###############################################################
#  Generated by:      Cadence Innovus 21.14-s109_1
#  OS:                Linux x86_64(Host ID caen-vnc-mi06.engin.umich.edu)
#  Generated on:      Mon Apr  3 19:46:33 2023
#  Design:            decoder
#  Command:           write_lef_abstract /afs/umich.edu/class/eecs627/w23/groups/group4/CNN_LSTM/MEM/apr/decoder/data/decoder.lef -specifyTopLayer 4 -stripePin -PGpinLayers 4
###############################################################

VERSION 5.8 ;

BUSBITCHARS "[]" ;
DIVIDERCHAR "/" ;

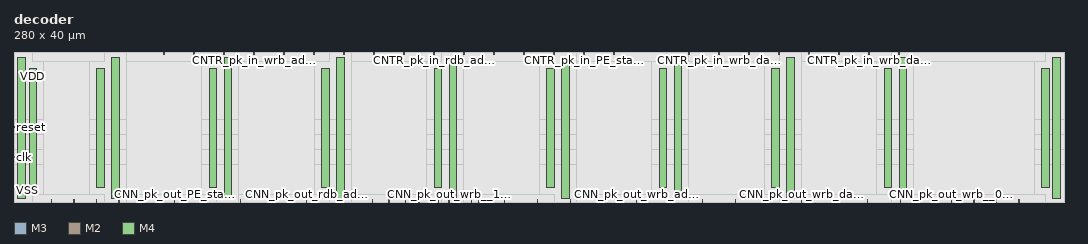
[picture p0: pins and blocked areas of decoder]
MACRO decoder
  CLASS BLOCK ;
  SIZE 280.000000 BY 40.000000 ;
  FOREIGN decoder 0.000000 0.000000 ;
  ORIGIN 0 0 ;
  SYMMETRY X Y R90 ;
  PIN clk
    DIRECTION INPUT ;
    USE SIGNAL ;
    ANTENNAPARTIALMETALAREA 1.46 LAYER M3  ;
    ANTENNAPARTIALMETALSIDEAREA 0.015 LAYER M3  ;
    ANTENNAMODEL OXIDE1 ;
    ANTENNAGATEAREA 0.2136 LAYER M3  ;
    ANTENNAMAXAREACAR 8.25187 LAYER M3  ;
    ANTENNAMAXSIDEAREACAR 0.0875468 LAYER M3  ;
    ANTENNAMAXCUTCAR 0.561798 LAYER V3  ;
    PORT
      LAYER M3 ;
        RECT 0.000000 11.900000 0.600000 12.100000 ;
    END
  END clk
  PIN reset
    DIRECTION INPUT ;
    USE SIGNAL ;
    ANTENNAPARTIALMETALAREA 12.66 LAYER M3  ;
    ANTENNAPARTIALMETALSIDEAREA 0.127 LAYER M3  ;
    ANTENNAMODEL OXIDE1 ;
    ANTENNAGATEAREA 0.4416 LAYER M3  ;
    ANTENNAMAXAREACAR 31.7705 LAYER M3  ;
    ANTENNAMAXSIDEAREACAR 0.316925 LAYER M3  ;
    ANTENNAMAXCUTCAR 0.48419 LAYER V3  ;
    PORT
      LAYER M3 ;
        RECT 0.000000 19.900000 0.600000 20.100000 ;
    END
  END reset
  PIN CNTR_pk_in_PE_state__2_
    DIRECTION INPUT ;
    USE SIGNAL ;
    ANTENNAPARTIALMETALAREA 1.66 LAYER M2  ;
    ANTENNAPARTIALMETALSIDEAREA 0.0166 LAYER M2  ;
    ANTENNAPARTIALCUTAREA 0.08 LAYER V2  ;
    ANTENNAPARTIALMETALAREA 0.36 LAYER M3  ;
    ANTENNAPARTIALMETALSIDEAREA 0.004 LAYER M3  ;
    ANTENNAMODEL OXIDE1 ;
    ANTENNAGATEAREA 0.0624 LAYER M3  ;
    ANTENNAMAXAREACAR 14.7692 LAYER M3  ;
    ANTENNAMAXSIDEAREACAR 0.155449 LAYER M3  ;
    ANTENNAMAXCUTCAR 2.5641 LAYER V3  ;
    PORT
      LAYER M2 ;
        RECT 135.900000 39.400000 136.100000 40.000000 ;
    END
  END CNTR_pk_in_PE_state__2_
  PIN CNTR_pk_in_PE_state__1_
    DIRECTION INPUT ;
    USE SIGNAL ;
    ANTENNAPARTIALMETALAREA 2.7 LAYER M2  ;
    ANTENNAPARTIALMETALSIDEAREA 0.027 LAYER M2  ;
    ANTENNAMODEL OXIDE1 ;
    ANTENNAGATEAREA 0.0624 LAYER M2  ;
    ANTENNAMAXAREACAR 49.0641 LAYER M2  ;
    ANTENNAMAXSIDEAREACAR 0.485577 LAYER M2  ;
    ANTENNAMAXCUTCAR 1.28205 LAYER V2  ;
    PORT
      LAYER M2 ;
        RECT 143.900000 39.400000 144.100000 40.000000 ;
    END
  END CNTR_pk_in_PE_state__1_
  PIN CNTR_pk_in_PE_state__0_
    DIRECTION INPUT ;
    USE SIGNAL ;
    ANTENNAPARTIALMETALAREA 2.62 LAYER M2  ;
    ANTENNAPARTIALMETALSIDEAREA 0.0262 LAYER M2  ;
    ANTENNAMODEL OXIDE1 ;
    ANTENNAGATEAREA 0.0624 LAYER M2  ;
    ANTENNAMAXAREACAR 47.7821 LAYER M2  ;
    ANTENNAMAXSIDEAREACAR 0.472756 LAYER M2  ;
    ANTENNAMAXCUTCAR 1.28205 LAYER V2  ;
    PORT
      LAYER M2 ;
        RECT 151.900000 39.400000 152.100000 40.000000 ;
    END
  END CNTR_pk_in_PE_state__0_
  PIN CNTR_pk_in_wrb_data__7_
    DIRECTION INPUT ;
    USE SIGNAL ;
    ANTENNAPARTIALMETALAREA 1.34 LAYER M2  ;
    ANTENNAPARTIALMETALSIDEAREA 0.0134 LAYER M2  ;
    ANTENNAPARTIALCUTAREA 0.08 LAYER V2  ;
    ANTENNAPARTIALMETALAREA 1.56 LAYER M3  ;
    ANTENNAPARTIALMETALSIDEAREA 0.016 LAYER M3  ;
    ANTENNAMODEL OXIDE1 ;
    ANTENNAGATEAREA 0.0624 LAYER M3  ;
    ANTENNAMAXAREACAR 39.1282 LAYER M3  ;
    ANTENNAMAXSIDEAREACAR 0.399038 LAYER M3  ;
    ANTENNAMAXCUTCAR 2.5641 LAYER V3  ;
    PORT
      LAYER M2 ;
        RECT 235.900000 39.400000 236.100000 40.000000 ;
    END
  END CNTR_pk_in_wrb_data__7_
  PIN CNTR_pk_in_wrb_data__6_
    DIRECTION INPUT ;
    USE SIGNAL ;
    ANTENNAPARTIALMETALAREA 2.7 LAYER M2  ;
    ANTENNAPARTIALMETALSIDEAREA 0.027 LAYER M2  ;
    ANTENNAMODEL OXIDE1 ;
    ANTENNAGATEAREA 0.0624 LAYER M2  ;
    ANTENNAMAXAREACAR 49.0641 LAYER M2  ;
    ANTENNAMAXSIDEAREACAR 0.485577 LAYER M2  ;
    ANTENNAMAXCUTCAR 1.28205 LAYER V2  ;
    PORT
      LAYER M2 ;
        RECT 227.900000 39.400000 228.100000 40.000000 ;
    END
  END CNTR_pk_in_wrb_data__6_
  PIN CNTR_pk_in_wrb_data__5_
    DIRECTION INPUT ;
    USE SIGNAL ;
    ANTENNAPARTIALMETALAREA 2.7 LAYER M2  ;
    ANTENNAPARTIALMETALSIDEAREA 0.027 LAYER M2  ;
    ANTENNAMODEL OXIDE1 ;
    ANTENNAGATEAREA 0.0624 LAYER M2  ;
    ANTENNAMAXAREACAR 49.0641 LAYER M2  ;
    ANTENNAMAXSIDEAREACAR 0.485577 LAYER M2  ;
    ANTENNAMAXCUTCAR 1.28205 LAYER V2  ;
    PORT
      LAYER M2 ;
        RECT 219.900000 39.400000 220.100000 40.000000 ;
    END
  END CNTR_pk_in_wrb_data__5_
  PIN CNTR_pk_in_wrb_data__4_
    DIRECTION INPUT ;
    USE SIGNAL ;
    ANTENNAPARTIALMETALAREA 2.7 LAYER M2  ;
    ANTENNAPARTIALMETALSIDEAREA 0.027 LAYER M2  ;
    ANTENNAMODEL OXIDE1 ;
    ANTENNAGATEAREA 0.0624 LAYER M2  ;
    ANTENNAMAXAREACAR 49.0641 LAYER M2  ;
    ANTENNAMAXSIDEAREACAR 0.485577 LAYER M2  ;
    ANTENNAMAXCUTCAR 1.28205 LAYER V2  ;
    PORT
      LAYER M2 ;
        RECT 211.900000 39.400000 212.100000 40.000000 ;
    END
  END CNTR_pk_in_wrb_data__4_
  PIN CNTR_pk_in_wrb_data__3_
    DIRECTION INPUT ;
    USE SIGNAL ;
    ANTENNAPARTIALMETALAREA 2.78 LAYER M2  ;
    ANTENNAPARTIALMETALSIDEAREA 0.0278 LAYER M2  ;
    ANTENNAMODEL OXIDE1 ;
    ANTENNAGATEAREA 0.0624 LAYER M2  ;
    ANTENNAMAXAREACAR 50.3462 LAYER M2  ;
    ANTENNAMAXSIDEAREACAR 0.498397 LAYER M2  ;
    ANTENNAMAXCUTCAR 1.28205 LAYER V2  ;
    PORT
      LAYER M2 ;
        RECT 203.900000 39.400000 204.100000 40.000000 ;
    END
  END CNTR_pk_in_wrb_data__3_
  PIN CNTR_pk_in_wrb_data__2_
    DIRECTION INPUT ;
    USE SIGNAL ;
    ANTENNAPARTIALMETALAREA 1.66 LAYER M2  ;
    ANTENNAPARTIALMETALSIDEAREA 0.0166 LAYER M2  ;
    ANTENNAPARTIALCUTAREA 0.08 LAYER V2  ;
    ANTENNAPARTIALMETALAREA 0.52 LAYER M3  ;
    ANTENNAPARTIALMETALSIDEAREA 0.0056 LAYER M3  ;
    ANTENNAMODEL OXIDE1 ;
    ANTENNAGATEAREA 0.0624 LAYER M3  ;
    ANTENNAMAXAREACAR 31.4359 LAYER M3  ;
    ANTENNAMAXSIDEAREACAR 0.322115 LAYER M3  ;
    ANTENNAMAXCUTCAR 2.5641 LAYER V3  ;
    PORT
      LAYER M2 ;
        RECT 195.900000 39.400000 196.100000 40.000000 ;
    END
  END CNTR_pk_in_wrb_data__2_
  PIN CNTR_pk_in_wrb_data__1_
    DIRECTION INPUT ;
    USE SIGNAL ;
    ANTENNAPARTIALMETALAREA 2.62 LAYER M2  ;
    ANTENNAPARTIALMETALSIDEAREA 0.0262 LAYER M2  ;
    ANTENNAMODEL OXIDE1 ;
    ANTENNAGATEAREA 0.0624 LAYER M2  ;
    ANTENNAMAXAREACAR 47.7821 LAYER M2  ;
    ANTENNAMAXSIDEAREACAR 0.472756 LAYER M2  ;
    ANTENNAMAXCUTCAR 1.28205 LAYER V2  ;
    PORT
      LAYER M2 ;
        RECT 187.900000 39.400000 188.100000 40.000000 ;
    END
  END CNTR_pk_in_wrb_data__1_
  PIN CNTR_pk_in_wrb_data__0_
    DIRECTION INPUT ;
    USE SIGNAL ;
    ANTENNAPARTIALMETALAREA 2.7 LAYER M2  ;
    ANTENNAPARTIALMETALSIDEAREA 0.027 LAYER M2  ;
    ANTENNAMODEL OXIDE1 ;
    ANTENNAGATEAREA 0.0624 LAYER M2  ;
    ANTENNAMAXAREACAR 49.0641 LAYER M2  ;
    ANTENNAMAXSIDEAREACAR 0.485577 LAYER M2  ;
    ANTENNAMAXCUTCAR 1.28205 LAYER V2  ;
    PORT
      LAYER M2 ;
        RECT 179.900000 39.400000 180.100000 40.000000 ;
    END
  END CNTR_pk_in_wrb_data__0_
  PIN CNTR_pk_in_wrb_addr__7_
    DIRECTION INPUT ;
    USE SIGNAL ;
    ANTENNAPARTIALMETALAREA 1.9 LAYER M2  ;
    ANTENNAPARTIALMETALSIDEAREA 0.019 LAYER M2  ;
    ANTENNAPARTIALCUTAREA 0.08 LAYER V2  ;
    ANTENNAPARTIALMETALAREA 5.76 LAYER M3  ;
    ANTENNAPARTIALMETALSIDEAREA 0.0584 LAYER M3  ;
    ANTENNAMODEL OXIDE1 ;
    ANTENNAGATEAREA 0.5184 LAYER M3  ;
    ANTENNAMAXAREACAR 17.4621 LAYER M3  ;
    ANTENNAMAXSIDEAREACAR 0.177783 LAYER M3  ;
    ANTENNAMAXCUTCAR 0.704225 LAYER V3  ;
    PORT
      LAYER M2 ;
        RECT 39.900000 39.400000 40.100000 40.000000 ;
    END
  END CNTR_pk_in_wrb_addr__7_
  PIN CNTR_pk_in_wrb_addr__6_
    DIRECTION INPUT ;
    USE SIGNAL ;
    ANTENNAPARTIALMETALAREA 1.42 LAYER M2  ;
    ANTENNAPARTIALMETALSIDEAREA 0.0142 LAYER M2  ;
    ANTENNAPARTIALCUTAREA 0.08 LAYER V2  ;
    ANTENNAPARTIALMETALAREA 1.4 LAYER M3  ;
    ANTENNAPARTIALMETALSIDEAREA 0.0144 LAYER M3  ;
    ANTENNAMODEL OXIDE1 ;
    ANTENNAGATEAREA 0.2208 LAYER M3  ;
    ANTENNAMAXAREACAR 21.8349 LAYER M3  ;
    ANTENNAMAXSIDEAREACAR 0.225215 LAYER M3  ;
    ANTENNAMAXCUTCAR 0.812769 LAYER V3  ;
    PORT
      LAYER M2 ;
        RECT 47.900000 39.400000 48.100000 40.000000 ;
    END
  END CNTR_pk_in_wrb_addr__6_
  PIN CNTR_pk_in_wrb_addr__5_
    DIRECTION INPUT ;
    USE SIGNAL ;
    ANTENNAPARTIALMETALAREA 1.34 LAYER M2  ;
    ANTENNAPARTIALMETALSIDEAREA 0.0134 LAYER M2  ;
    ANTENNAPARTIALCUTAREA 0.08 LAYER V2  ;
    ANTENNAPARTIALMETALAREA 1.16 LAYER M3  ;
    ANTENNAPARTIALMETALSIDEAREA 0.012 LAYER M3  ;
    ANTENNAMODEL OXIDE1 ;
    ANTENNAGATEAREA 0.0888 LAYER M3  ;
    ANTENNAMAXAREACAR 20.464 LAYER M3  ;
    ANTENNAMAXSIDEAREACAR 0.216892 LAYER M3  ;
    ANTENNAMAXCUTCAR 1.35135 LAYER V3  ;
    PORT
      LAYER M2 ;
        RECT 55.900000 39.400000 56.100000 40.000000 ;
    END
  END CNTR_pk_in_wrb_addr__5_
  PIN CNTR_pk_in_wrb_addr__4_
    DIRECTION INPUT ;
    USE SIGNAL ;
    ANTENNAPARTIALMETALAREA 1.9 LAYER M2  ;
    ANTENNAPARTIALMETALSIDEAREA 0.019 LAYER M2  ;
    ANTENNAMODEL OXIDE1 ;
    ANTENNAGATEAREA 0.1704 LAYER M2  ;
    ANTENNAMAXAREACAR 12.7277 LAYER M2  ;
    ANTENNAMAXSIDEAREACAR 0.127465 LAYER M2  ;
    ANTENNAPARTIALCUTAREA 0.08 LAYER V2  ;
    ANTENNAMAXCUTCAR 0.938967 LAYER V2  ;
    ANTENNAPARTIALMETALAREA 0.92 LAYER M3  ;
    ANTENNAPARTIALMETALSIDEAREA 0.0096 LAYER M3  ;
    ANTENNAGATEAREA 0.4512 LAYER M3  ;
    ANTENNAMAXAREACAR 14.7667 LAYER M3  ;
    ANTENNAMAXSIDEAREACAR 0.148741 LAYER M3  ;
    ANTENNAMAXCUTCAR 0.938967 LAYER V3  ;
    PORT
      LAYER M2 ;
        RECT 63.900000 39.400000 64.100000 40.000000 ;
    END
  END CNTR_pk_in_wrb_addr__4_
  PIN CNTR_pk_in_wrb_addr__3_
    DIRECTION INPUT ;
    USE SIGNAL ;
    ANTENNAPARTIALMETALAREA 2.0424 LAYER M2  ;
    ANTENNAPARTIALMETALSIDEAREA 0.02036 LAYER M2  ;
    ANTENNAPARTIALCUTAREA 0.08 LAYER V2  ;
    ANTENNAPARTIALMETALAREA 13 LAYER M3  ;
    ANTENNAPARTIALMETALSIDEAREA 0.1304 LAYER M3  ;
    ANTENNAPARTIALCUTAREA 0.04 LAYER V3  ;
    ANTENNAPARTIALMETALAREA 0.24 LAYER M4  ;
    ANTENNAPARTIALMETALSIDEAREA 0.0032 LAYER M4  ;
    ANTENNAMODEL OXIDE1 ;
    ANTENNAGATEAREA 0.0624 LAYER M4  ;
    ANTENNAMAXAREACAR 40.4103 LAYER M4  ;
    ANTENNAMAXSIDEAREACAR 0.424679 LAYER M4  ;
    ANTENNAMAXCUTCAR 3.20513 LAYER V4  ;
    PORT
      LAYER M2 ;
        RECT 71.920000 39.240000 72.080000 40.000000 ;
    END
  END CNTR_pk_in_wrb_addr__3_
  PIN CNTR_pk_in_wrb_addr__2_
    DIRECTION INPUT ;
    USE SIGNAL ;
    ANTENNAPARTIALMETALAREA 0.164 LAYER M2  ;
    ANTENNAPARTIALMETALSIDEAREA 0.00164 LAYER M2  ;
    ANTENNAPARTIALCUTAREA 0.08 LAYER V2  ;
    ANTENNAPARTIALMETALAREA 9.64 LAYER M3  ;
    ANTENNAPARTIALMETALSIDEAREA 0.0968 LAYER M3  ;
    ANTENNAPARTIALCUTAREA 0.04 LAYER V3  ;
    ANTENNAPARTIALMETALAREA 0.24 LAYER M4  ;
    ANTENNAPARTIALMETALSIDEAREA 0.0032 LAYER M4  ;
    ANTENNAMODEL OXIDE1 ;
    ANTENNAGATEAREA 0.0624 LAYER M4  ;
    ANTENNAMAXAREACAR 47.4615 LAYER M4  ;
    ANTENNAMAXSIDEAREACAR 0.501603 LAYER M4  ;
    ANTENNAMAXCUTCAR 3.20513 LAYER V4  ;
    PORT
      LAYER M2 ;
        RECT 79.920000 39.240000 80.080000 40.000000 ;
    END
  END CNTR_pk_in_wrb_addr__2_
  PIN CNTR_pk_in_wrb_addr__1_
    DIRECTION INPUT ;
    USE SIGNAL ;
    ANTENNAPARTIALMETALAREA 1.4824 LAYER M2  ;
    ANTENNAPARTIALMETALSIDEAREA 0.01476 LAYER M2  ;
    ANTENNAPARTIALCUTAREA 0.08 LAYER V2  ;
    ANTENNAPARTIALMETALAREA 6.8 LAYER M3  ;
    ANTENNAPARTIALMETALSIDEAREA 0.0688 LAYER M3  ;
    ANTENNAPARTIALCUTAREA 0.04 LAYER V3  ;
    ANTENNAPARTIALMETALAREA 0.24 LAYER M4  ;
    ANTENNAPARTIALMETALSIDEAREA 0.0032 LAYER M4  ;
    ANTENNAMODEL OXIDE1 ;
    ANTENNAGATEAREA 0.0624 LAYER M4  ;
    ANTENNAMAXAREACAR 36.5641 LAYER M4  ;
    ANTENNAMAXSIDEAREACAR 0.386218 LAYER M4  ;
    ANTENNAMAXCUTCAR 3.20513 LAYER V4  ;
    PORT
      LAYER M2 ;
        RECT 87.920000 39.240000 88.080000 40.000000 ;
    END
  END CNTR_pk_in_wrb_addr__1_
  PIN CNTR_pk_in_wrb_addr__0_
    DIRECTION INPUT ;
    USE SIGNAL ;
    ANTENNAPARTIALMETALAREA 2.46 LAYER M2  ;
    ANTENNAPARTIALMETALSIDEAREA 0.0246 LAYER M2  ;
    ANTENNAPARTIALCUTAREA 0.08 LAYER V2  ;
    ANTENNAPARTIALMETALAREA 5 LAYER M3  ;
    ANTENNAPARTIALMETALSIDEAREA 0.0504 LAYER M3  ;
    ANTENNAPARTIALCUTAREA 0.04 LAYER V3  ;
    ANTENNAPARTIALMETALAREA 0.24 LAYER M4  ;
    ANTENNAPARTIALMETALSIDEAREA 0.0032 LAYER M4  ;
    ANTENNAMODEL OXIDE1 ;
    ANTENNAGATEAREA 0.0624 LAYER M4  ;
    ANTENNAMAXAREACAR 31.4359 LAYER M4  ;
    ANTENNAMAXSIDEAREACAR 0.334936 LAYER M4  ;
    ANTENNAMAXCUTCAR 3.20513 LAYER V4  ;
    PORT
      LAYER M2 ;
        RECT 95.900000 39.400000 96.100000 40.000000 ;
    END
  END CNTR_pk_in_wrb_addr__0_
  PIN CNTR_pk_in_wrb_
    DIRECTION INPUT ;
    USE SIGNAL ;
    ANTENNAPARTIALMETALAREA 3.18 LAYER M2  ;
    ANTENNAPARTIALMETALSIDEAREA 0.0318 LAYER M2  ;
    ANTENNAPARTIALCUTAREA 0.08 LAYER V2  ;
    ANTENNAPARTIALMETALAREA 20.24 LAYER M3  ;
    ANTENNAPARTIALMETALSIDEAREA 0.2032 LAYER M3  ;
    ANTENNAMODEL OXIDE1 ;
    ANTENNAGATEAREA 0.4104 LAYER M3  ;
    ANTENNAMAXAREACAR 52.5131 LAYER M3  ;
    ANTENNAMAXSIDEAREACAR 0.536506 LAYER M3  ;
    ANTENNAMAXCUTCAR 1.72414 LAYER V3  ;
    PORT
      LAYER M2 ;
        RECT 159.900000 39.400000 160.100000 40.000000 ;
    END
  END CNTR_pk_in_wrb_
  PIN CNTR_pk_in_rdb_addr__3_
    DIRECTION INPUT ;
    USE SIGNAL ;
    ANTENNAPARTIALMETALAREA 1.5 LAYER M2  ;
    ANTENNAPARTIALMETALSIDEAREA 0.015 LAYER M2  ;
    ANTENNAPARTIALCUTAREA 0.08 LAYER V2  ;
    ANTENNAPARTIALMETALAREA 0.6 LAYER M3  ;
    ANTENNAPARTIALMETALSIDEAREA 0.0064 LAYER M3  ;
    ANTENNAMODEL OXIDE1 ;
    ANTENNAGATEAREA 0.0624 LAYER M3  ;
    ANTENNAMAXAREACAR 21.1795 LAYER M3  ;
    ANTENNAMAXSIDEAREACAR 0.219551 LAYER M3  ;
    ANTENNAMAXCUTCAR 2.5641 LAYER V3  ;
    PORT
      LAYER M2 ;
        RECT 103.900000 39.400000 104.100000 40.000000 ;
    END
  END CNTR_pk_in_rdb_addr__3_
  PIN CNTR_pk_in_rdb_addr__2_
    DIRECTION INPUT ;
    USE SIGNAL ;
    ANTENNAPARTIALMETALAREA 1.74 LAYER M2  ;
    ANTENNAPARTIALMETALSIDEAREA 0.0174 LAYER M2  ;
    ANTENNAMODEL OXIDE1 ;
    ANTENNAGATEAREA 0.0624 LAYER M2  ;
    ANTENNAMAXAREACAR 33.6795 LAYER M2  ;
    ANTENNAMAXSIDEAREACAR 0.331731 LAYER M2  ;
    ANTENNAMAXCUTCAR 1.28205 LAYER V2  ;
    PORT
      LAYER M2 ;
        RECT 111.900000 39.400000 112.100000 40.000000 ;
    END
  END CNTR_pk_in_rdb_addr__2_
  PIN CNTR_pk_in_rdb_addr__1_
    DIRECTION INPUT ;
    USE SIGNAL ;
    ANTENNAPARTIALMETALAREA 1.92 LAYER M2  ;
    ANTENNAPARTIALMETALSIDEAREA 0.0192 LAYER M2  ;
    ANTENNAMODEL OXIDE1 ;
    ANTENNAGATEAREA 0.0624 LAYER M2  ;
    ANTENNAMAXAREACAR 36.5641 LAYER M2  ;
    ANTENNAMAXSIDEAREACAR 0.360577 LAYER M2  ;
    ANTENNAMAXCUTCAR 1.28205 LAYER V2  ;
    PORT
      LAYER M2 ;
        RECT 119.900000 39.400000 120.100000 40.000000 ;
    END
  END CNTR_pk_in_rdb_addr__1_
  PIN CNTR_pk_in_rdb_addr__0_
    DIRECTION INPUT ;
    USE SIGNAL ;
    ANTENNAPARTIALMETALAREA 3.18 LAYER M2  ;
    ANTENNAPARTIALMETALSIDEAREA 0.0318 LAYER M2  ;
    ANTENNAMODEL OXIDE1 ;
    ANTENNAGATEAREA 0.0624 LAYER M2  ;
    ANTENNAMAXAREACAR 56.7564 LAYER M2  ;
    ANTENNAMAXSIDEAREACAR 0.5625 LAYER M2  ;
    ANTENNAMAXCUTCAR 1.28205 LAYER V2  ;
    PORT
      LAYER M2 ;
        RECT 127.900000 39.400000 128.100000 40.000000 ;
    END
  END CNTR_pk_in_rdb_addr__0_
  PIN CNN_pk_out_PE_state__2_
    DIRECTION OUTPUT ;
    USE SIGNAL ;
    ANTENNAPARTIALMETALAREA 1.26 LAYER M2  ;
    ANTENNAPARTIALMETALSIDEAREA 0.0126 LAYER M2  ;
    ANTENNAPARTIALCUTAREA 0.08 LAYER V2  ;
    ANTENNADIFFAREA 2.014 LAYER M3  ;
    ANTENNAPARTIALMETALAREA 7.8 LAYER M3  ;
    ANTENNAPARTIALMETALSIDEAREA 0.0784 LAYER M3  ;
    PORT
      LAYER M2 ;
        RECT 60.300000 0.000000 60.500000 0.600000 ;
    END
  END CNN_pk_out_PE_state__2_
  PIN CNN_pk_out_PE_state__1_
    DIRECTION OUTPUT ;
    USE SIGNAL ;
    ANTENNAPARTIALMETALAREA 1.42 LAYER M2  ;
    ANTENNAPARTIALMETALSIDEAREA 0.0142 LAYER M2  ;
    ANTENNAPARTIALCUTAREA 0.08 LAYER V2  ;
    ANTENNADIFFAREA 2.014 LAYER M3  ;
    ANTENNAPARTIALMETALAREA 3.8 LAYER M3  ;
    ANTENNAPARTIALMETALSIDEAREA 0.0384 LAYER M3  ;
    PORT
      LAYER M2 ;
        RECT 51.500000 0.000000 51.700000 0.600000 ;
    END
  END CNN_pk_out_PE_state__1_
  PIN CNN_pk_out_PE_state__0_
    DIRECTION OUTPUT ;
    USE SIGNAL ;
    ANTENNADIFFAREA 2.014 LAYER M2  ;
    ANTENNAPARTIALMETALAREA 5.58 LAYER M2  ;
    ANTENNAPARTIALMETALSIDEAREA 0.0558 LAYER M2  ;
    PORT
      LAYER M2 ;
        RECT 42.700000 0.000000 42.900000 0.600000 ;
    END
  END CNN_pk_out_PE_state__0_
  PIN CNN_pk_out_wrb_data__7_
    DIRECTION OUTPUT ;
    USE SIGNAL ;
    ANTENNAPARTIALMETALAREA 1.66 LAYER M2  ;
    ANTENNAPARTIALMETALSIDEAREA 0.0166 LAYER M2  ;
    ANTENNAPARTIALCUTAREA 0.08 LAYER V2  ;
    ANTENNADIFFAREA 2.014 LAYER M3  ;
    ANTENNAPARTIALMETALAREA 1.16 LAYER M3  ;
    ANTENNAPARTIALMETALSIDEAREA 0.012 LAYER M3  ;
    PORT
      LAYER M2 ;
        RECT 236.300000 0.000000 236.500000 0.600000 ;
    END
  END CNN_pk_out_wrb_data__7_
  PIN CNN_pk_out_wrb_data__6_
    DIRECTION OUTPUT ;
    USE SIGNAL ;
    ANTENNAPARTIALMETALAREA 2.94 LAYER M2  ;
    ANTENNAPARTIALMETALSIDEAREA 0.0294 LAYER M2  ;
    ANTENNAPARTIALCUTAREA 0.08 LAYER V2  ;
    ANTENNADIFFAREA 2.014 LAYER M3  ;
    ANTENNAPARTIALMETALAREA 0.68 LAYER M3  ;
    ANTENNAPARTIALMETALSIDEAREA 0.0072 LAYER M3  ;
    PORT
      LAYER M2 ;
        RECT 227.500000 0.000000 227.700000 0.600000 ;
    END
  END CNN_pk_out_wrb_data__6_
  PIN CNN_pk_out_wrb_data__5_
    DIRECTION OUTPUT ;
    USE SIGNAL ;
    ANTENNAPARTIALMETALAREA 3.74 LAYER M2  ;
    ANTENNAPARTIALMETALSIDEAREA 0.0374 LAYER M2  ;
    ANTENNAPARTIALCUTAREA 0.08 LAYER V2  ;
    ANTENNADIFFAREA 2.014 LAYER M3  ;
    ANTENNAPARTIALMETALAREA 0.76 LAYER M3  ;
    ANTENNAPARTIALMETALSIDEAREA 0.008 LAYER M3  ;
    PORT
      LAYER M2 ;
        RECT 218.700000 0.000000 218.900000 0.600000 ;
    END
  END CNN_pk_out_wrb_data__5_
  PIN CNN_pk_out_wrb_data__4_
    DIRECTION OUTPUT ;
    USE SIGNAL ;
    ANTENNAPARTIALMETALAREA 3.58 LAYER M2  ;
    ANTENNAPARTIALMETALSIDEAREA 0.0358 LAYER M2  ;
    ANTENNAPARTIALCUTAREA 0.08 LAYER V2  ;
    ANTENNADIFFAREA 2.014 LAYER M3  ;
    ANTENNAPARTIALMETALAREA 0.76 LAYER M3  ;
    ANTENNAPARTIALMETALSIDEAREA 0.008 LAYER M3  ;
    PORT
      LAYER M2 ;
        RECT 209.900000 0.000000 210.100000 0.600000 ;
    END
  END CNN_pk_out_wrb_data__4_
  PIN CNN_pk_out_wrb_data__3_
    DIRECTION OUTPUT ;
    USE SIGNAL ;
    ANTENNADIFFAREA 2.014 LAYER M2  ;
    ANTENNAPARTIALMETALAREA 4.56 LAYER M2  ;
    ANTENNAPARTIALMETALSIDEAREA 0.0456 LAYER M2  ;
    PORT
      LAYER M2 ;
        RECT 201.100000 0.000000 201.300000 0.600000 ;
    END
  END CNN_pk_out_wrb_data__3_
  PIN CNN_pk_out_wrb_data__2_
    DIRECTION OUTPUT ;
    USE SIGNAL ;
    ANTENNADIFFAREA 2.014 LAYER M2  ;
    ANTENNAPARTIALMETALAREA 4.06 LAYER M2  ;
    ANTENNAPARTIALMETALSIDEAREA 0.0406 LAYER M2  ;
    PORT
      LAYER M2 ;
        RECT 192.300000 0.000000 192.500000 0.600000 ;
    END
  END CNN_pk_out_wrb_data__2_
  PIN CNN_pk_out_wrb_data__1_
    DIRECTION OUTPUT ;
    USE SIGNAL ;
    ANTENNAPARTIALMETALAREA 3.74 LAYER M2  ;
    ANTENNAPARTIALMETALSIDEAREA 0.0374 LAYER M2  ;
    ANTENNAPARTIALCUTAREA 0.08 LAYER V2  ;
    ANTENNADIFFAREA 2.014 LAYER M3  ;
    ANTENNAPARTIALMETALAREA 0.92 LAYER M3  ;
    ANTENNAPARTIALMETALSIDEAREA 0.0096 LAYER M3  ;
    PORT
      LAYER M2 ;
        RECT 183.500000 0.000000 183.700000 0.600000 ;
    END
  END CNN_pk_out_wrb_data__1_
  PIN CNN_pk_out_wrb_data__0_
    DIRECTION OUTPUT ;
    USE SIGNAL ;
    ANTENNADIFFAREA 2.014 LAYER M2  ;
    ANTENNAPARTIALMETALAREA 4.38 LAYER M2  ;
    ANTENNAPARTIALMETALSIDEAREA 0.0438 LAYER M2  ;
    PORT
      LAYER M2 ;
        RECT 174.700000 0.000000 174.900000 0.600000 ;
    END
  END CNN_pk_out_wrb_data__0_
  PIN CNN_pk_out_wrb_addr__3_
    DIRECTION OUTPUT ;
    USE SIGNAL ;
    ANTENNADIFFAREA 2.014 LAYER M2  ;
    ANTENNAPARTIALMETALAREA 4.16 LAYER M2  ;
    ANTENNAPARTIALMETALSIDEAREA 0.0416 LAYER M2  ;
    PORT
      LAYER M2 ;
        RECT 165.900000 0.000000 166.100000 0.600000 ;
    END
  END CNN_pk_out_wrb_addr__3_
  PIN CNN_pk_out_wrb_addr__2_
    DIRECTION OUTPUT ;
    USE SIGNAL ;
    ANTENNAPARTIALMETALAREA 3.82 LAYER M2  ;
    ANTENNAPARTIALMETALSIDEAREA 0.0382 LAYER M2  ;
    ANTENNAPARTIALCUTAREA 0.08 LAYER V2  ;
    ANTENNADIFFAREA 2.014 LAYER M3  ;
    ANTENNAPARTIALMETALAREA 0.76 LAYER M3  ;
    ANTENNAPARTIALMETALSIDEAREA 0.008 LAYER M3  ;
    PORT
      LAYER M2 ;
        RECT 157.100000 0.000000 157.300000 0.600000 ;
    END
  END CNN_pk_out_wrb_addr__2_
  PIN CNN_pk_out_wrb_addr__1_
    DIRECTION OUTPUT ;
    USE SIGNAL ;
    ANTENNAPARTIALMETALAREA 2.86 LAYER M2  ;
    ANTENNAPARTIALMETALSIDEAREA 0.0286 LAYER M2  ;
    ANTENNAPARTIALCUTAREA 0.08 LAYER V2  ;
    ANTENNADIFFAREA 2.014 LAYER M3  ;
    ANTENNAPARTIALMETALAREA 0.68 LAYER M3  ;
    ANTENNAPARTIALMETALSIDEAREA 0.0072 LAYER M3  ;
    PORT
      LAYER M2 ;
        RECT 148.300000 0.000000 148.500000 0.600000 ;
    END
  END CNN_pk_out_wrb_addr__1_
  PIN CNN_pk_out_wrb_addr__0_
    DIRECTION OUTPUT ;
    USE SIGNAL ;
    ANTENNAPARTIALMETALAREA 2.78 LAYER M2  ;
    ANTENNAPARTIALMETALSIDEAREA 0.0278 LAYER M2  ;
    ANTENNAPARTIALCUTAREA 0.08 LAYER V2  ;
    ANTENNADIFFAREA 2.014 LAYER M3  ;
    ANTENNAPARTIALMETALAREA 0.6 LAYER M3  ;
    ANTENNAPARTIALMETALSIDEAREA 0.0064 LAYER M3  ;
    PORT
      LAYER M2 ;
        RECT 139.500000 0.000000 139.700000 0.600000 ;
    END
  END CNN_pk_out_wrb_addr__0_
  PIN CNN_pk_out_wrb__3__3_
    DIRECTION OUTPUT ;
    USE SIGNAL ;
    ANTENNAPARTIALMETALAREA 1.42 LAYER M2  ;
    ANTENNAPARTIALMETALSIDEAREA 0.0142 LAYER M2  ;
    ANTENNAPARTIALCUTAREA 0.08 LAYER V2  ;
    ANTENNADIFFAREA 2.172 LAYER M3  ;
    ANTENNAPARTIALMETALAREA 2.04 LAYER M3  ;
    ANTENNAPARTIALMETALSIDEAREA 0.0208 LAYER M3  ;
    PORT
      LAYER M2 ;
        RECT 130.700000 0.000000 130.900000 0.600000 ;
    END
  END CNN_pk_out_wrb__3__3_
  PIN CNN_pk_out_wrb__3__2_
    DIRECTION OUTPUT ;
    USE SIGNAL ;
    ANTENNADIFFAREA 2.172 LAYER M2  ;
    ANTENNAPARTIALMETALAREA 2.78 LAYER M2  ;
    ANTENNAPARTIALMETALSIDEAREA 0.0278 LAYER M2  ;
    PORT
      LAYER M2 ;
        RECT 121.900000 0.000000 122.100000 0.600000 ;
    END
  END CNN_pk_out_wrb__3__2_
  PIN CNN_pk_out_wrb__3__1_
    DIRECTION OUTPUT ;
    USE SIGNAL ;
    ANTENNAPARTIALMETALAREA 1.26 LAYER M2  ;
    ANTENNAPARTIALMETALSIDEAREA 0.0126 LAYER M2  ;
    ANTENNAPARTIALCUTAREA 0.08 LAYER V2  ;
    ANTENNADIFFAREA 3.196 LAYER M3  ;
    ANTENNAPARTIALMETALAREA 1.72 LAYER M3  ;
    ANTENNAPARTIALMETALSIDEAREA 0.0176 LAYER M3  ;
    PORT
      LAYER M2 ;
        RECT 113.100000 0.000000 113.300000 0.600000 ;
    END
  END CNN_pk_out_wrb__3__1_
  PIN CNN_pk_out_wrb__3__0_
    DIRECTION OUTPUT ;
    USE SIGNAL ;
    ANTENNAPARTIALMETALAREA 1.98 LAYER M2  ;
    ANTENNAPARTIALMETALSIDEAREA 0.0198 LAYER M2  ;
    ANTENNAPARTIALCUTAREA 0.04 LAYER V2  ;
    ANTENNADIFFAREA 3.196 LAYER M3  ;
    ANTENNAPARTIALMETALAREA 0.28 LAYER M3  ;
    ANTENNAPARTIALMETALSIDEAREA 0.0032 LAYER M3  ;
    PORT
      LAYER M2 ;
        RECT 104.300000 0.000000 104.500000 0.600000 ;
    END
  END CNN_pk_out_wrb__3__0_
  PIN CNN_pk_out_wrb__2__3_
    DIRECTION OUTPUT ;
    USE SIGNAL ;
    ANTENNAPARTIALMETALAREA 1.34 LAYER M2  ;
    ANTENNAPARTIALMETALSIDEAREA 0.0134 LAYER M2  ;
    ANTENNAPARTIALCUTAREA 0.08 LAYER V2  ;
    ANTENNADIFFAREA 2.172 LAYER M3  ;
    ANTENNAPARTIALMETALAREA 1.48 LAYER M3  ;
    ANTENNAPARTIALMETALSIDEAREA 0.0152 LAYER M3  ;
    PORT
      LAYER M2 ;
        RECT 27.900000 0.000000 28.100000 0.600000 ;
    END
  END CNN_pk_out_wrb__2__3_
  PIN CNN_pk_out_wrb__2__2_
    DIRECTION OUTPUT ;
    USE SIGNAL ;
    ANTENNAPARTIALMETALAREA 2.54 LAYER M2  ;
    ANTENNAPARTIALMETALSIDEAREA 0.0254 LAYER M2  ;
    ANTENNAPARTIALCUTAREA 0.08 LAYER V2  ;
    ANTENNADIFFAREA 2.172 LAYER M3  ;
    ANTENNAPARTIALMETALAREA 2.76 LAYER M3  ;
    ANTENNAPARTIALMETALSIDEAREA 0.028 LAYER M3  ;
    PORT
      LAYER M2 ;
        RECT 21.900000 0.000000 22.100000 0.600000 ;
    END
  END CNN_pk_out_wrb__2__2_
  PIN CNN_pk_out_wrb__2__1_
    DIRECTION OUTPUT ;
    USE SIGNAL ;
    ANTENNAPARTIALMETALAREA 1.5 LAYER M2  ;
    ANTENNAPARTIALMETALSIDEAREA 0.015 LAYER M2  ;
    ANTENNAPARTIALCUTAREA 0.08 LAYER V2  ;
    ANTENNADIFFAREA 3.196 LAYER M3  ;
    ANTENNAPARTIALMETALAREA 6.12 LAYER M3  ;
    ANTENNAPARTIALMETALSIDEAREA 0.0616 LAYER M3  ;
    PORT
      LAYER M2 ;
        RECT 15.900000 0.000000 16.100000 0.600000 ;
    END
  END CNN_pk_out_wrb__2__1_
  PIN CNN_pk_out_wrb__2__0_
    DIRECTION OUTPUT ;
    USE SIGNAL ;
    ANTENNAPARTIALMETALAREA 0.7 LAYER M2  ;
    ANTENNAPARTIALMETALSIDEAREA 0.007 LAYER M2  ;
    ANTENNAPARTIALCUTAREA 0.08 LAYER V2  ;
    ANTENNADIFFAREA 3.196 LAYER M3  ;
    ANTENNAPARTIALMETALAREA 7.56 LAYER M3  ;
    ANTENNAPARTIALMETALSIDEAREA 0.076 LAYER M3  ;
    PORT
      LAYER M2 ;
        RECT 9.900000 0.000000 10.100000 0.600000 ;
    END
  END CNN_pk_out_wrb__2__0_
  PIN CNN_pk_out_wrb__1__3_
    DIRECTION OUTPUT ;
    USE SIGNAL ;
    ANTENNADIFFAREA 2.172 LAYER M2  ;
    ANTENNAPARTIALMETALAREA 2.62 LAYER M2  ;
    ANTENNAPARTIALMETALSIDEAREA 0.0262 LAYER M2  ;
    PORT
      LAYER M2 ;
        RECT 123.900000 0.000000 124.100000 0.600000 ;
    END
  END CNN_pk_out_wrb__1__3_
  PIN CNN_pk_out_wrb__1__2_
    DIRECTION OUTPUT ;
    USE SIGNAL ;
    ANTENNADIFFAREA 2.172 LAYER M2  ;
    ANTENNAPARTIALMETALAREA 1.5 LAYER M2  ;
    ANTENNAPARTIALMETALSIDEAREA 0.015 LAYER M2  ;
    PORT
      LAYER M2 ;
        RECT 115.900000 0.000000 116.100000 0.600000 ;
    END
  END CNN_pk_out_wrb__1__2_
  PIN CNN_pk_out_wrb__1__1_
    DIRECTION OUTPUT ;
    USE SIGNAL ;
    ANTENNAPARTIALMETALAREA 1.98 LAYER M2  ;
    ANTENNAPARTIALMETALSIDEAREA 0.0198 LAYER M2  ;
    ANTENNAPARTIALCUTAREA 0.08 LAYER V2  ;
    ANTENNADIFFAREA 3.196 LAYER M3  ;
    ANTENNAPARTIALMETALAREA 0.52 LAYER M3  ;
    ANTENNAPARTIALMETALSIDEAREA 0.0056 LAYER M3  ;
    PORT
      LAYER M2 ;
        RECT 107.900000 0.000000 108.100000 0.600000 ;
    END
  END CNN_pk_out_wrb__1__1_
  PIN CNN_pk_out_wrb__1__0_
    DIRECTION OUTPUT ;
    USE SIGNAL ;
    ANTENNAPARTIALMETALAREA 1.5 LAYER M2  ;
    ANTENNAPARTIALMETALSIDEAREA 0.015 LAYER M2  ;
    ANTENNAPARTIALCUTAREA 0.04 LAYER V2  ;
    ANTENNADIFFAREA 3.196 LAYER M3  ;
    ANTENNAPARTIALMETALAREA 0.84 LAYER M3  ;
    ANTENNAPARTIALMETALSIDEAREA 0.0088 LAYER M3  ;
    PORT
      LAYER M2 ;
        RECT 99.900000 0.000000 100.100000 0.600000 ;
    END
  END CNN_pk_out_wrb__1__0_
  PIN CNN_pk_out_wrb__0__3_
    DIRECTION OUTPUT ;
    USE SIGNAL ;
    ANTENNAPARTIALMETALAREA 2.46 LAYER M2  ;
    ANTENNAPARTIALMETALSIDEAREA 0.0246 LAYER M2  ;
    ANTENNAPARTIALCUTAREA 0.08 LAYER V2  ;
    ANTENNADIFFAREA 2.848 LAYER M3  ;
    ANTENNAPARTIALMETALAREA 23.48 LAYER M3  ;
    ANTENNAPARTIALMETALSIDEAREA 0.2352 LAYER M3  ;
    PORT
      LAYER M2 ;
        RECT 267.900000 0.000000 268.100000 0.600000 ;
    END
  END CNN_pk_out_wrb__0__3_
  PIN CNN_pk_out_wrb__0__2_
    DIRECTION OUTPUT ;
    USE SIGNAL ;
    ANTENNAPARTIALMETALAREA 1.42 LAYER M2  ;
    ANTENNAPARTIALMETALSIDEAREA 0.0142 LAYER M2  ;
    ANTENNAPARTIALCUTAREA 0.08 LAYER V2  ;
    ANTENNADIFFAREA 2.848 LAYER M3  ;
    ANTENNAPARTIALMETALAREA 23.72 LAYER M3  ;
    ANTENNAPARTIALMETALSIDEAREA 0.2376 LAYER M3  ;
    PORT
      LAYER M2 ;
        RECT 261.900000 0.000000 262.100000 0.600000 ;
    END
  END CNN_pk_out_wrb__0__2_
  PIN CNN_pk_out_wrb__0__1_
    DIRECTION OUTPUT ;
    USE SIGNAL ;
    ANTENNAPARTIALMETALAREA 1.82 LAYER M2  ;
    ANTENNAPARTIALMETALSIDEAREA 0.0182 LAYER M2  ;
    ANTENNAPARTIALCUTAREA 0.08 LAYER V2  ;
    ANTENNADIFFAREA 4.548 LAYER M3  ;
    ANTENNAPARTIALMETALAREA 23.16 LAYER M3  ;
    ANTENNAPARTIALMETALSIDEAREA 0.232 LAYER M3  ;
    PORT
      LAYER M2 ;
        RECT 255.900000 0.000000 256.100000 0.600000 ;
    END
  END CNN_pk_out_wrb__0__1_
  PIN CNN_pk_out_wrb__0__0_
    DIRECTION OUTPUT ;
    USE SIGNAL ;
    ANTENNAPARTIALMETALAREA 2.14 LAYER M2  ;
    ANTENNAPARTIALMETALSIDEAREA 0.0214 LAYER M2  ;
    ANTENNAPARTIALCUTAREA 0.08 LAYER V2  ;
    ANTENNADIFFAREA 4.548 LAYER M3  ;
    ANTENNAPARTIALMETALAREA 22.6 LAYER M3  ;
    ANTENNAPARTIALMETALSIDEAREA 0.2264 LAYER M3  ;
    PORT
      LAYER M2 ;
        RECT 249.900000 0.000000 250.100000 0.600000 ;
    END
  END CNN_pk_out_wrb__0__0_
  PIN CNN_pk_out_rdb_addr__3_
    DIRECTION OUTPUT ;
    USE SIGNAL ;
    ANTENNAPARTIALMETALAREA 2.86 LAYER M2  ;
    ANTENNAPARTIALMETALSIDEAREA 0.0286 LAYER M2  ;
    ANTENNAPARTIALCUTAREA 0.08 LAYER V2  ;
    ANTENNADIFFAREA 2.014 LAYER M3  ;
    ANTENNAPARTIALMETALAREA 1.32 LAYER M3  ;
    ANTENNAPARTIALMETALSIDEAREA 0.0136 LAYER M3  ;
    PORT
      LAYER M2 ;
        RECT 95.500000 0.000000 95.700000 0.600000 ;
    END
  END CNN_pk_out_rdb_addr__3_
  PIN CNN_pk_out_rdb_addr__2_
    DIRECTION OUTPUT ;
    USE SIGNAL ;
    ANTENNAPARTIALMETALAREA 1.5 LAYER M2  ;
    ANTENNAPARTIALMETALSIDEAREA 0.015 LAYER M2  ;
    ANTENNAPARTIALCUTAREA 0.08 LAYER V2  ;
    ANTENNADIFFAREA 2.014 LAYER M3  ;
    ANTENNAPARTIALMETALAREA 0.6 LAYER M3  ;
    ANTENNAPARTIALMETALSIDEAREA 0.0064 LAYER M3  ;
    PORT
      LAYER M2 ;
        RECT 86.700000 0.000000 86.900000 0.600000 ;
    END
  END CNN_pk_out_rdb_addr__2_
  PIN CNN_pk_out_rdb_addr__1_
    DIRECTION OUTPUT ;
    USE SIGNAL ;
    ANTENNADIFFAREA 2.014 LAYER M2  ;
    ANTENNAPARTIALMETALAREA 5.9 LAYER M2  ;
    ANTENNAPARTIALMETALSIDEAREA 0.059 LAYER M2  ;
    PORT
      LAYER M2 ;
        RECT 77.900000 0.000000 78.100000 0.600000 ;
    END
  END CNN_pk_out_rdb_addr__1_
  PIN CNN_pk_out_rdb_addr__0_
    DIRECTION OUTPUT ;
    USE SIGNAL ;
    ANTENNAPARTIALMETALAREA 3.58 LAYER M2  ;
    ANTENNAPARTIALMETALSIDEAREA 0.0358 LAYER M2  ;
    ANTENNAPARTIALCUTAREA 0.08 LAYER V2  ;
    ANTENNADIFFAREA 2.014 LAYER M3  ;
    ANTENNAPARTIALMETALAREA 10.36 LAYER M3  ;
    ANTENNAPARTIALMETALSIDEAREA 0.104 LAYER M3  ;
    PORT
      LAYER M2 ;
        RECT 69.100000 0.000000 69.300000 0.600000 ;
    END
  END CNN_pk_out_rdb_addr__0_
  PIN VSS
    DIRECTION INOUT ;
    USE GROUND ;

# P/G power stripe data as pin
    PORT
      LAYER M4 ;
        RECT 1.000000 1.000000 3.000000 38.600000 ;
        RECT 26.000000 1.000000 28.000000 38.600000 ;
        RECT 56.000000 1.000000 58.000000 38.600000 ;
        RECT 116.000000 1.000000 118.000000 38.600000 ;
        RECT 86.000000 1.000000 88.000000 38.600000 ;
        RECT 206.000000 1.000000 208.000000 38.600000 ;
        RECT 176.000000 1.000000 178.000000 38.600000 ;
        RECT 146.000000 1.000000 148.000000 38.600000 ;
        RECT 236.000000 1.000000 238.000000 38.600000 ;
        RECT 277.000000 1.000000 279.000000 38.600000 ;
    END
# end of P/G power stripe data as pin

  END VSS
  PIN VDD
    DIRECTION INOUT ;
    USE POWER ;

# P/G power stripe data as pin
    PORT
      LAYER M4 ;
        RECT 4.000000 4.000000 6.000000 35.600000 ;
        RECT 22.000000 4.000000 24.000000 35.600000 ;
        RECT 52.000000 4.000000 54.000000 35.600000 ;
        RECT 112.000000 4.000000 114.000000 35.600000 ;
        RECT 82.000000 4.000000 84.000000 35.600000 ;
        RECT 202.000000 4.000000 204.000000 35.600000 ;
        RECT 172.000000 4.000000 174.000000 35.600000 ;
        RECT 142.000000 4.000000 144.000000 35.600000 ;
        RECT 232.000000 4.000000 234.000000 35.600000 ;
        RECT 274.000000 4.000000 276.000000 35.600000 ;
    END
# end of P/G power stripe data as pin

  END VDD
  OBS
    LAYER M1 ;
      RECT 0.000000 0.000000 280.000000 40.000000 ;
    LAYER M2 ;
      RECT 238.020000 37.480000 280.000000 40.000000 ;
      RECT 230.020000 37.480000 233.980000 40.000000 ;
      RECT 222.020000 37.480000 225.980000 40.000000 ;
      RECT 214.020000 37.480000 217.980000 40.000000 ;
      RECT 206.020000 37.480000 209.980000 40.000000 ;
      RECT 198.020000 37.480000 201.980000 40.000000 ;
      RECT 190.020000 37.480000 193.980000 40.000000 ;
      RECT 182.020000 37.480000 185.980000 40.000000 ;
      RECT 162.020000 37.480000 177.980000 40.000000 ;
      RECT 154.020000 37.480000 157.980000 40.000000 ;
      RECT 146.020000 37.480000 149.980000 40.000000 ;
      RECT 138.020000 37.480000 141.980000 40.000000 ;
      RECT 130.020000 37.480000 133.980000 40.000000 ;
      RECT 122.020000 37.480000 125.980000 40.000000 ;
      RECT 114.020000 37.480000 117.980000 40.000000 ;
      RECT 106.020000 37.480000 109.980000 40.000000 ;
      RECT 98.020000 37.480000 101.980000 40.000000 ;
      RECT 90.000000 37.480000 93.980000 40.000000 ;
      RECT 66.020000 37.480000 70.000000 40.000000 ;
      RECT 58.020000 37.480000 61.980000 40.000000 ;
      RECT 50.020000 37.480000 53.980000 40.000000 ;
      RECT 42.020000 37.480000 45.980000 40.000000 ;
      RECT 0.000000 37.480000 37.980000 40.000000 ;
      RECT 90.000000 37.320000 280.000000 37.480000 ;
      RECT 82.000000 37.320000 86.000000 40.000000 ;
      RECT 74.000000 37.320000 78.000000 40.000000 ;
      RECT 0.000000 37.320000 70.000000 37.480000 ;
      RECT 0.000000 2.520000 280.000000 37.320000 ;
      RECT 270.020000 0.000000 280.000000 2.520000 ;
      RECT 264.020000 0.000000 265.980000 2.520000 ;
      RECT 258.020000 0.000000 259.980000 2.520000 ;
      RECT 252.020000 0.000000 253.980000 2.520000 ;
      RECT 238.420000 0.000000 247.980000 2.520000 ;
      RECT 229.620000 0.000000 234.380000 2.520000 ;
      RECT 220.820000 0.000000 225.580000 2.520000 ;
      RECT 212.020000 0.000000 216.780000 2.520000 ;
      RECT 203.220000 0.000000 207.980000 2.520000 ;
      RECT 194.420000 0.000000 199.180000 2.520000 ;
      RECT 185.620000 0.000000 190.380000 2.520000 ;
      RECT 176.820000 0.000000 181.580000 2.520000 ;
      RECT 168.020000 0.000000 172.780000 2.520000 ;
      RECT 159.220000 0.000000 163.980000 2.520000 ;
      RECT 150.420000 0.000000 155.180000 2.520000 ;
      RECT 141.620000 0.000000 146.380000 2.520000 ;
      RECT 132.820000 0.000000 137.580000 2.520000 ;
      RECT 126.020000 0.000000 128.780000 2.520000 ;
      RECT 118.020000 0.000000 119.980000 2.520000 ;
      RECT 110.020000 0.000000 111.180000 2.520000 ;
      RECT 102.020000 0.000000 102.380000 2.520000 ;
      RECT 97.620000 0.000000 97.980000 2.520000 ;
      RECT 88.820000 0.000000 93.580000 2.520000 ;
      RECT 80.020000 0.000000 84.780000 2.520000 ;
      RECT 71.220000 0.000000 75.980000 2.520000 ;
      RECT 62.420000 0.000000 67.180000 2.520000 ;
      RECT 53.620000 0.000000 58.380000 2.520000 ;
      RECT 44.820000 0.000000 49.580000 2.520000 ;
      RECT 30.020000 0.000000 40.780000 2.520000 ;
      RECT 24.020000 0.000000 25.980000 2.520000 ;
      RECT 18.020000 0.000000 19.980000 2.520000 ;
      RECT 12.020000 0.000000 13.980000 2.520000 ;
      RECT 0.000000 0.000000 7.980000 2.520000 ;
    LAYER M3 ;
      RECT 0.000000 22.020000 280.000000 40.000000 ;
      RECT 2.520000 17.980000 280.000000 22.020000 ;
      RECT 0.000000 14.020000 280.000000 17.980000 ;
      RECT 2.520000 9.980000 280.000000 14.020000 ;
      RECT 0.000000 0.000000 280.000000 9.980000 ;
    LAYER M4 ;
      RECT 239.920000 37.520000 275.080000 40.000000 ;
      RECT 209.920000 37.520000 234.080000 40.000000 ;
      RECT 179.920000 37.520000 204.080000 40.000000 ;
      RECT 149.920000 37.520000 174.080000 40.000000 ;
      RECT 119.920000 37.520000 144.080000 40.000000 ;
      RECT 89.920000 37.520000 114.080000 40.000000 ;
      RECT 59.920000 37.520000 84.080000 40.000000 ;
      RECT 29.920000 37.520000 54.080000 40.000000 ;
      RECT 4.920000 37.520000 24.080000 40.000000 ;
      RECT 239.920000 2.080000 272.080000 37.520000 ;
      RECT 209.920000 2.080000 230.080000 37.520000 ;
      RECT 179.920000 2.080000 200.080000 37.520000 ;
      RECT 149.920000 2.080000 170.080000 37.520000 ;
      RECT 119.920000 2.080000 140.080000 37.520000 ;
      RECT 89.920000 2.080000 110.080000 37.520000 ;
      RECT 59.920000 2.080000 80.080000 37.520000 ;
      RECT 29.920000 2.080000 50.080000 37.520000 ;
      RECT 7.920000 2.080000 20.080000 37.520000 ;
      RECT 239.920000 0.000000 275.080000 2.080000 ;
      RECT 209.920000 0.000000 234.080000 2.080000 ;
      RECT 179.920000 0.000000 204.080000 2.080000 ;
      RECT 149.920000 0.000000 174.080000 2.080000 ;
      RECT 119.920000 0.000000 144.080000 2.080000 ;
      RECT 89.920000 0.000000 114.080000 2.080000 ;
      RECT 59.920000 0.000000 84.080000 2.080000 ;
      RECT 29.920000 0.000000 54.080000 2.080000 ;
      RECT 4.920000 0.000000 24.080000 2.080000 ;
  END
END decoder

END LIBRARY
